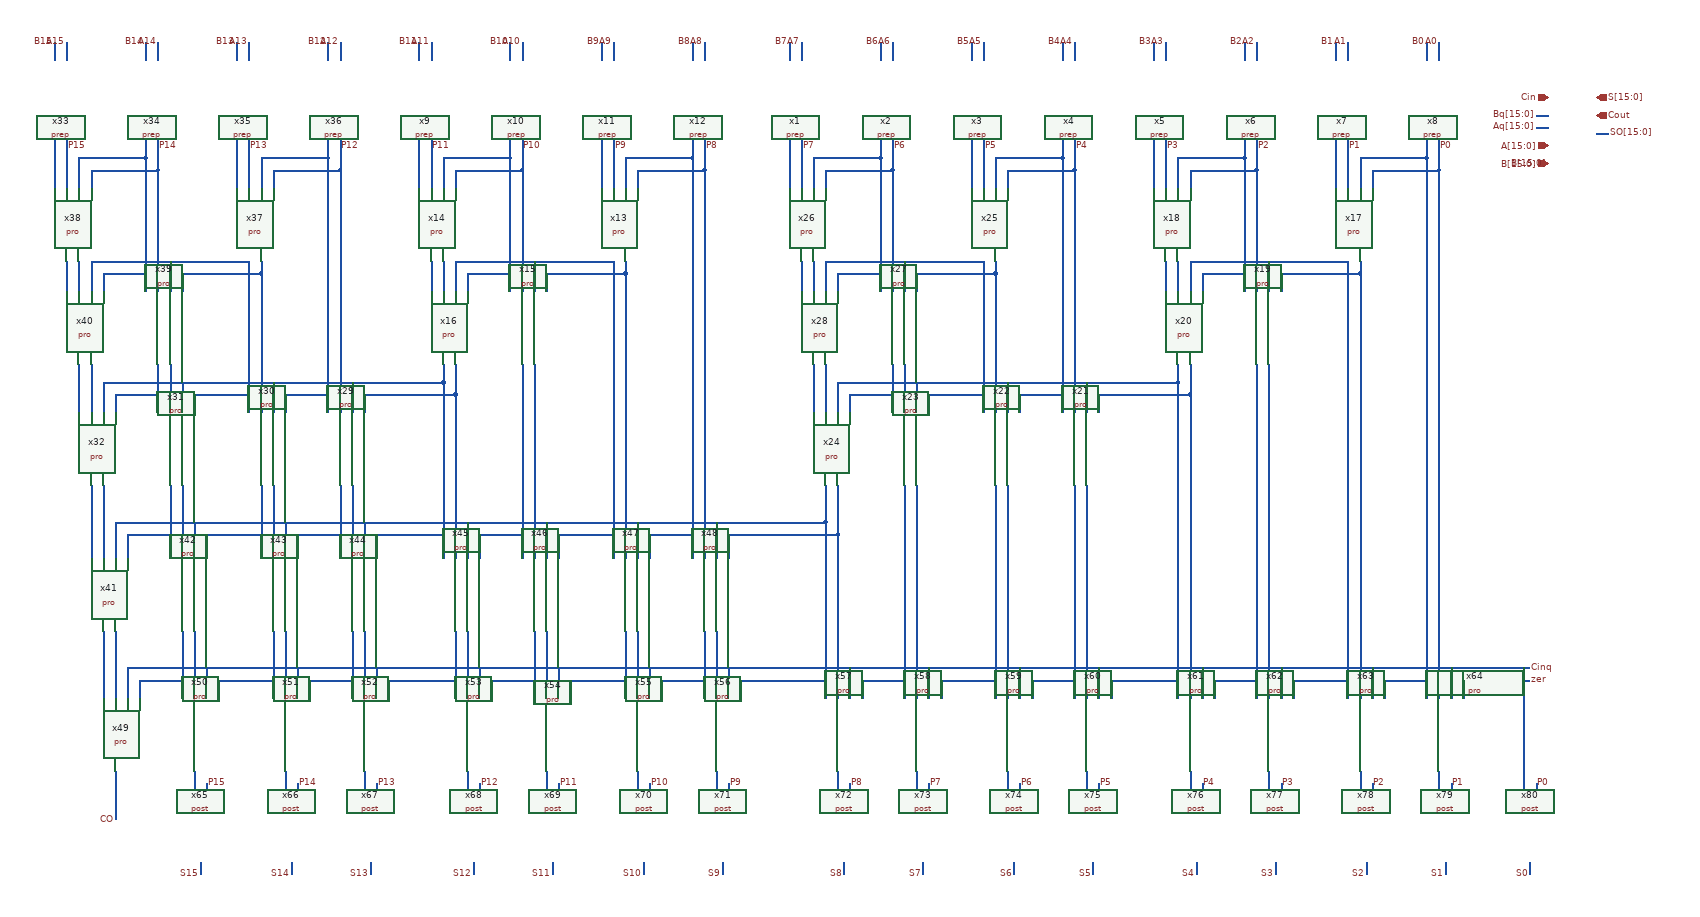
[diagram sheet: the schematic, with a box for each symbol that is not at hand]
v {xschem version=3.4.6 file_version=1.2}
G {}
K {}
V {}
S {}
E {}
N 1130 10 1130 60 {lab=P0}
N 1020 60 1020 90 {lab=P0}
N 1110 10 1110 40 {lab=#net1}
N 1000 40 1000 90 {lab=#net1}
N 980 10 980 90 {lab=P1}
N 960 10 960 90 {lab=#net2}
N 1000 40 1110 40 {lab=#net1}
N 1020 60 1130 60 {lab=P0}
N 660 10 660 90 {lab=#net3}
N 680 10 680 90 {lab=P3}
N 700 40 700 90 {lab=#net4}
N 700 40 810 40 {lab=#net4}
N 810 10 810 40 {lab=#net4}
N 830 10 830 60 {lab=P2}
N 720 60 830 60 {lab=P2}
N 720 60 720 90 {lab=P2}
N 680 210 680 260 {lab=#net5}
N 700 210 700 260 {lab=#net6}
N 720 210 720 260 {lab=#net7}
N 720 210 980 210 {lab=#net7}
N 740 230 740 260 {lab=#net8}
N 740 230 1000 230 {lab=#net8}
N 1000 210 1000 230 {lab=#net8}
N 810 40 810 250 {lab=#net4}
N 830 60 830 250 {lab=P2}
N 850 210 850 250 {lab=#net7}
N 530 10 530 60 {lab=P4}
N 420 60 420 90 {lab=P4}
N 510 10 510 40 {lab=#net9}
N 400 40 400 90 {lab=#net9}
N 380 10 380 90 {lab=P5}
N 360 10 360 90 {lab=#net10}
N 400 40 510 40 {lab=#net9}
N 420 60 530 60 {lab=P4}
N 60 10 60 90 {lab=#net11}
N 80 10 80 90 {lab=P7}
N 100 40 100 90 {lab=#net12}
N 100 40 210 40 {lab=#net12}
N 210 10 210 40 {lab=#net12}
N 230 10 230 60 {lab=P6}
N 120 60 230 60 {lab=P6}
N 120 60 120 90 {lab=P6}
N 80 210 80 260 {lab=#net13}
N 100 210 100 260 {lab=#net14}
N 120 210 120 260 {lab=#net15}
N 120 210 380 210 {lab=#net15}
N 140 230 140 260 {lab=#net16}
N 140 230 400 230 {lab=#net16}
N 400 210 400 230 {lab=#net16}
N 210 40 210 250 {lab=#net12}
N 230 60 230 250 {lab=P6}
N 250 210 250 250 {lab=#net15}
N 210 250 210 260 {lab=#net12}
N 230 250 230 260 {lab=P6}
N 250 250 250 260 {lab=#net15}
N 810 250 810 260 {lab=#net4}
N 830 250 830 260 {lab=P2}
N 850 250 850 260 {lab=#net7}
N 700 380 700 410 {lab=#net17}
N 140 410 700 410 {lab=#net17}
N 140 410 140 460 {lab=#net17}
N 720 380 720 430 {lab=#net18}
N 160 430 720 430 {lab=#net18}
N 160 430 160 460 {lab=#net18}
N 100 380 100 460 {lab=#net19}
N 120 380 120 460 {lab=#net20}
N 230 380 230 460 {lab=#net21}
N 250 380 250 460 {lab=#net22}
N 270 410 270 460 {lab=#net17}
N 290 430 290 460 {lab=#net18}
N 380 210 380 460 {lab=#net15}
N 400 230 400 460 {lab=#net16}
N 420 410 420 460 {lab=#net17}
N 440 430 440 460 {lab=#net18}
N 510 40 510 460 {lab=#net9}
N 530 60 530 460 {lab=P4}
N 550 410 550 460 {lab=#net17}
N 570 430 570 460 {lab=#net18}
N -80 10 -80 60 {lab=P8}
N -190 60 -190 90 {lab=P8}
N -100 10 -100 40 {lab=#net23}
N -210 40 -210 90 {lab=#net23}
N -230 10 -230 90 {lab=P9}
N -250 10 -250 90 {lab=#net24}
N -210 40 -100 40 {lab=#net23}
N -190 60 -80 60 {lab=P8}
N -550 10 -550 90 {lab=#net25}
N -530 10 -530 90 {lab=P11}
N -510 40 -510 90 {lab=#net26}
N -510 40 -400 40 {lab=#net26}
N -400 10 -400 40 {lab=#net26}
N -380 10 -380 60 {lab=P10}
N -490 60 -380 60 {lab=P10}
N -490 60 -490 90 {lab=P10}
N -530 210 -530 260 {lab=#net27}
N -510 210 -510 260 {lab=#net28}
N -490 210 -490 260 {lab=#net29}
N -490 210 -230 210 {lab=#net29}
N -470 230 -470 260 {lab=#net30}
N -470 230 -210 230 {lab=#net30}
N -210 210 -210 230 {lab=#net30}
N -400 40 -400 250 {lab=#net26}
N -380 60 -380 250 {lab=P10}
N -360 210 -360 250 {lab=#net29}
N -680 10 -680 60 {lab=P12}
N -790 60 -790 90 {lab=P12}
N -700 10 -700 40 {lab=#net31}
N -810 40 -810 90 {lab=#net31}
N -830 10 -830 90 {lab=P13}
N -850 10 -850 90 {lab=#net32}
N -810 40 -700 40 {lab=#net31}
N -790 60 -680 60 {lab=P12}
N -1150 10 -1150 90 {lab=#net33}
N -1130 10 -1130 90 {lab=P15}
N -1110 40 -1110 90 {lab=#net34}
N -1110 40 -1000 40 {lab=#net34}
N -1000 10 -1000 40 {lab=#net34}
N -980 10 -980 60 {lab=P14}
N -1090 60 -980 60 {lab=P14}
N -1090 60 -1090 90 {lab=P14}
N -1130 210 -1130 260 {lab=#net35}
N -1110 210 -1110 260 {lab=#net36}
N -1090 210 -1090 260 {lab=#net37}
N -1090 210 -830 210 {lab=#net37}
N -1070 230 -1070 260 {lab=#net38}
N -1070 230 -810 230 {lab=#net38}
N -810 210 -810 230 {lab=#net38}
N -1000 40 -1000 250 {lab=#net34}
N -980 60 -980 250 {lab=P14}
N -960 210 -960 250 {lab=#net37}
N -1000 250 -1000 260 {lab=#net34}
N -980 250 -980 260 {lab=P14}
N -960 250 -960 260 {lab=#net37}
N -400 250 -400 260 {lab=#net26}
N -380 250 -380 260 {lab=P10}
N -360 250 -360 260 {lab=#net29}
N -510 380 -510 410 {lab=#net39}
N -1070 410 -510 410 {lab=#net39}
N -1070 410 -1070 460 {lab=#net39}
N -490 380 -490 430 {lab=#net40}
N -1050 430 -490 430 {lab=#net40}
N -1050 430 -1050 460 {lab=#net40}
N -1110 380 -1110 460 {lab=#net41}
N -1090 380 -1090 460 {lab=#net42}
N -980 380 -980 460 {lab=#net43}
N -960 380 -960 460 {lab=#net44}
N -940 410 -940 460 {lab=#net39}
N -920 430 -920 460 {lab=#net40}
N -830 210 -830 460 {lab=#net37}
N -810 230 -810 460 {lab=#net38}
N -790 410 -790 460 {lab=#net39}
N -770 430 -770 460 {lab=#net40}
N -700 40 -700 460 {lab=#net31}
N -680 60 -680 460 {lab=P12}
N -660 410 -660 460 {lab=#net39}
N -640 430 -640 460 {lab=#net40}
N -1090 580 -1090 700 {lab=#net45}
N -1070 580 -1070 700 {lab=#net46}
N -960 580 -960 700 {lab=#net47}
N -940 580 -940 700 {lab=#net48}
N -810 580 -810 700 {lab=#net49}
N -790 580 -790 700 {lab=#net50}
N -680 580 -680 700 {lab=#net51}
N -660 580 -660 700 {lab=#net52}
N -510 410 -510 700 {lab=#net39}
N -490 430 -490 700 {lab=#net40}
N -380 380 -380 700 {lab=#net53}
N -360 380 -360 700 {lab=#net54}
N -230 210 -230 700 {lab=#net29}
N -210 230 -210 700 {lab=#net30}
N -100 40 -100 700 {lab=#net23}
N -80 60 -80 700 {lab=P8}
N 120 580 120 640 {lab=#net55}
N -1050 640 120 640 {lab=#net55}
N -1050 640 -1050 700 {lab=#net55}
N -1030 660 -1030 700 {lab=#net56}
N -1030 660 140 660 {lab=#net56}
N 140 580 140 660 {lab=#net56}
N -40 660 -40 700 {lab=#net56}
N -60 640 -60 700 {lab=#net55}
N -170 660 -170 700 {lab=#net56}
N -190 640 -190 700 {lab=#net55}
N -320 660 -320 700 {lab=#net56}
N -340 640 -340 700 {lab=#net55}
N -450 660 -450 700 {lab=#net56}
N -470 640 -470 700 {lab=#net55}
N -620 660 -620 700 {lab=#net56}
N -640 640 -640 700 {lab=#net55}
N -750 660 -750 700 {lab=#net56}
N -770 640 -770 700 {lab=#net55}
N -900 660 -900 700 {lab=#net56}
N -920 640 -920 700 {lab=#net55}
N -1070 820 -1070 930 {lab=#net57}
N -1050 820 -1050 930 {lab=#net58}
N -940 820 -940 930 {lab=#net59}
N -920 820 -920 930 {lab=#net60}
N -790 820 -790 930 {lab=#net61}
N -770 820 -770 930 {lab=#net62}
N -660 820 -660 930 {lab=#net63}
N -640 820 -640 930 {lab=#net64}
N -490 820 -490 930 {lab=#net65}
N -470 820 -470 930 {lab=#net66}
N -360 820 -360 940 {lab=#net67}
N -340 820 -340 930 {lab=#net68}
N -210 820 -210 930 {lab=#net69}
N -190 820 -190 930 {lab=#net70}
N -80 820 -80 930 {lab=#net71}
N -60 820 -60 930 {lab=#net72}
N 120 640 120 930 {lab=#net55}
N 140 660 140 930 {lab=#net56}
N 250 580 250 930 {lab=#net73}
N 270 580 270 930 {lab=#net74}
N 400 580 400 930 {lab=#net75}
N 420 580 420 930 {lab=#net76}
N 530 580 530 930 {lab=#net77}
N 550 580 550 930 {lab=#net78}
N 700 410 700 930 {lab=#net17}
N 720 430 720 930 {lab=#net18}
N 830 380 830 930 {lab=#net79}
N 850 380 850 930 {lab=#net80}
N 980 210 980 930 {lab=#net7}
N 1000 230 1000 930 {lab=#net8}
N 1110 40 1110 930 {lab=#net1}
N 1130 60 1130 930 {lab=P0}
N -1030 880 -1030 930 {lab=Cin}
N -1030 880 1280 880 {lab=Cin}
N -1010 900 -1010 930 {lab=zer}
N -1010 900 1280 900 {lab=zer}
N 1170 900 1170 930 {lab=zer}
N 1150 880 1150 930 {lab=Cin}
N 1040 900 1040 930 {lab=zer}
N 1020 880 1020 930 {lab=Cin}
N 890 900 890 930 {lab=zer}
N 870 880 870 930 {lab=Cin}
N 740 880 740 930 {lab=Cin}
N 760 900 760 930 {lab=zer}
N 590 900 590 930 {lab=zer}
N 570 880 570 930 {lab=Cin}
N 460 900 460 930 {lab=zer}
N 440 880 440 930 {lab=Cin}
N 310 900 310 930 {lab=zer}
N 290 880 290 930 {lab=Cin}
N 180 900 180 930 {lab=zer}
N 160 880 160 930 {lab=Cin}
N -20 900 -20 930 {lab=zer}
N -40 880 -40 930 {lab=Cin}
N -150 900 -150 930 {lab=zer}
N -170 880 -170 930 {lab=Cin}
N -300 900 -300 930 {lab=zer}
N -320 880 -320 930 {lab=Cin}
N -430 900 -430 930 {lab=zer}
N -450 880 -450 930 {lab=Cin}
N -600 900 -600 930 {lab=zer}
N -620 880 -620 930 {lab=Cin}
N -730 900 -730 930 {lab=zer}
N -750 880 -750 930 {lab=Cin}
N -880 900 -880 930 {lab=zer}
N -900 880 -900 930 {lab=Cin}
N -1050 1050 -1050 1130 {lab=Cout}
N -920 1050 -920 1080 {lab=#net81}
N -770 1050 -770 1080 {lab=#net82}
N -640 1050 -640 1080 {lab=#net83}
N -470 1050 -470 1080 {lab=#net84}
N -340 1050 -340 1080 {lab=#net85}
N -190 1050 -190 1080 {lab=#net86}
N -60 1050 -60 1080 {lab=#net87}
N 140 1050 140 1080 {lab=#net88}
N 270 1050 270 1080 {lab=#net89}
N 420 1050 420 1080 {lab=#net90}
N 550 1050 550 1080 {lab=#net91}
N 720 1050 720 1080 {lab=#net92}
N 850 1050 850 1080 {lab=#net93}
N 1000 1050 1000 1080 {lab=#net94}
N 1130 1050 1130 1080 {lab=#net95}
N -1150 -150 -1150 -120 {lab=B15}
N -1130 -150 -1130 -120 {lab=A15}
N -1000 -150 -1000 -120 {lab=B14}
N -980 -150 -980 -120 {lab=A14}
N -850 -150 -850 -120 {lab=B13}
N -830 -150 -830 -120 {lab=A13}
N -700 -150 -700 -120 {lab=B12}
N -680 -150 -680 -120 {lab=A12}
N -550 -150 -550 -120 {lab=B11}
N -530 -150 -530 -120 {lab=A11}
N -400 -150 -400 -120 {lab=B10}
N -380 -150 -380 -120 {lab=A10}
N -250 -150 -250 -120 {lab=B9}
N -230 -150 -230 -120 {lab=A9}
N -100 -150 -100 -120 {lab=B8}
N -80 -150 -80 -120 {lab=A8}
N 60 -150 60 -120 {lab=B7}
N 80 -150 80 -120 {lab=A7}
N 210 -150 210 -120 {lab=B6}
N 230 -150 230 -120 {lab=A6}
N 360 -150 360 -120 {lab=B5}
N 380 -150 380 -120 {lab=A5}
N 510 -150 510 -120 {lab=B4}
N 530 -150 530 -120 {lab=A4}
N 660 -150 660 -120 {lab=B3}
N 680 -150 680 -120 {lab=A3}
N 810 -150 810 -120 {lab=B2}
N 830 -150 830 -120 {lab=A2}
N 960 -150 960 -120 {lab=B1}
N 980 -150 980 -120 {lab=A1}
N 1110 -150 1110 -120 {lab=B0}
N 1130 -150 1130 -120 {lab=A0}
N 1270 880 1270 1080 {lab=Cin}
N 1290 1070 1290 1080 {lab=P0}
N 1150 1070 1150 1080 {lab=P1}
N 1020 1070 1020 1080 {lab=P2}
N 870 1070 870 1080 {lab=P3}
N 740 1070 740 1080 {lab=P4}
N 570 1070 570 1080 {lab=P5}
N 440 1070 440 1080 {lab=P6}
N 290 1070 290 1080 {lab=P7}
N 160 1070 160 1080 {lab=P8}
N -40 1070 -40 1080 {lab=P9}
N -170 1070 -170 1080 {lab=P10}
N -320 1070 -320 1080 {lab=P11}
N -450 1070 -450 1080 {lab=P12}
N -620 1070 -620 1080 {lab=P13}
N -750 1070 -750 1080 {lab=P14}
N -900 1070 -900 1080 {lab=P15}
N 1280 1200 1280 1220 {lab=S0}
N 1140 1200 1140 1220 {lab=S1}
N 1010 1200 1010 1220 {lab=S2}
N 860 1200 860 1220 {lab=S3}
N 730 1200 730 1220 {lab=S4}
N 560 1200 560 1220 {lab=S5}
N 430 1200 430 1220 {lab=S6}
N 280 1200 280 1220 {lab=S7}
N 150 1200 150 1220 {lab=S8}
N -50 1200 -50 1220 {lab=S9}
N -180 1200 -180 1220 {lab=S10}
N -330 1200 -330 1220 {lab=S11}
N -460 1200 -460 1220 {lab=S12}
N -630 1200 -630 1220 {lab=S13}
N -760 1200 -760 1220 {lab=S14}
N -910 1200 -910 1220 {lab=S15}
N 270 230 270 260 {lab=#net16}
N -940 230 -940 260 {lab=#net38}
N -340 230 -340 260 {lab=#net30}
N 870 230 870 260 {lab=#net8}
N 1290 -10 1310 -10 {lab=#net96}
N 1290 -30 1310 -30 {lab=#net97}
N 1390 0 1410 0 {lab=#net97}
C {/home/EE23B038/ee5311/tutorial_9/prep.sym} 660 -40 0 0 {name=x5}
C {/home/EE23B038/ee5311/tutorial_9/prep.sym} 810 -40 0 0 {name=x6}
C {/home/EE23B038/ee5311/tutorial_9/prep.sym} 960 -40 0 0 {name=x7}
C {/home/EE23B038/ee5311/tutorial_9/prep.sym} 1110 -40 0 0 {name=x8}
C {/home/EE23B038/ee5311/tutorial_9/pro.sym} 970 160 0 0 {name=x17}
C {/home/EE23B038/ee5311/tutorial_9/pro.sym} 670 160 0 0 {name=x18}
C {/home/EE23B038/ee5311/tutorial_9/pro.sym} 820 330 0 0 {name=x19}
C {/home/EE23B038/ee5311/tutorial_9/pro.sym} 690 330 0 0 {name=x20}
C {/home/EE23B038/ee5311/tutorial_9/pro.sym} 520 530 0 0 {name=x21}
C {/home/EE23B038/ee5311/tutorial_9/pro.sym} 390 530 0 0 {name=x22}
C {/home/EE23B038/ee5311/tutorial_9/pro.sym} 240 530 0 0 {name=x23}
C {/home/EE23B038/ee5311/tutorial_9/pro.sym} 110 530 0 0 {name=x24}
C {/home/EE23B038/ee5311/tutorial_9/prep.sym} 60 -40 0 0 {name=x1}
C {/home/EE23B038/ee5311/tutorial_9/prep.sym} 210 -40 0 0 {name=x2}
C {/home/EE23B038/ee5311/tutorial_9/prep.sym} 360 -40 0 0 {name=x3}
C {/home/EE23B038/ee5311/tutorial_9/prep.sym} 510 -40 0 0 {name=x4}
C {/home/EE23B038/ee5311/tutorial_9/pro.sym} 370 160 0 0 {name=x25}
C {/home/EE23B038/ee5311/tutorial_9/pro.sym} 70 160 0 0 {name=x26}
C {/home/EE23B038/ee5311/tutorial_9/pro.sym} 220 330 0 0 {name=x27}
C {/home/EE23B038/ee5311/tutorial_9/pro.sym} 90 330 0 0 {name=x28}
C {/home/EE23B038/ee5311/tutorial_9/prep.sym} -550 -40 0 0 {name=x9}
C {/home/EE23B038/ee5311/tutorial_9/prep.sym} -400 -40 0 0 {name=x10}
C {/home/EE23B038/ee5311/tutorial_9/prep.sym} -250 -40 0 0 {name=x11}
C {/home/EE23B038/ee5311/tutorial_9/prep.sym} -100 -40 0 0 {name=x12}
C {/home/EE23B038/ee5311/tutorial_9/pro.sym} -240 160 0 0 {name=x13}
C {/home/EE23B038/ee5311/tutorial_9/pro.sym} -540 160 0 0 {name=x14}
C {/home/EE23B038/ee5311/tutorial_9/pro.sym} -390 330 0 0 {name=x15}
C {/home/EE23B038/ee5311/tutorial_9/pro.sym} -520 330 0 0 {name=x16}
C {/home/EE23B038/ee5311/tutorial_9/pro.sym} -690 530 0 0 {name=x29}
C {/home/EE23B038/ee5311/tutorial_9/pro.sym} -820 530 0 0 {name=x30}
C {/home/EE23B038/ee5311/tutorial_9/pro.sym} -970 530 0 0 {name=x31}
C {/home/EE23B038/ee5311/tutorial_9/pro.sym} -1100 530 0 0 {name=x32}
C {/home/EE23B038/ee5311/tutorial_9/prep.sym} -1150 -40 0 0 {name=x33}
C {/home/EE23B038/ee5311/tutorial_9/prep.sym} -1000 -40 0 0 {name=x34}
C {/home/EE23B038/ee5311/tutorial_9/prep.sym} -850 -40 0 0 {name=x35}
C {/home/EE23B038/ee5311/tutorial_9/prep.sym} -700 -40 0 0 {name=x36}
C {/home/EE23B038/ee5311/tutorial_9/pro.sym} -840 160 0 0 {name=x37}
C {/home/EE23B038/ee5311/tutorial_9/pro.sym} -1140 160 0 0 {name=x38}
C {/home/EE23B038/ee5311/tutorial_9/pro.sym} -990 330 0 0 {name=x39}
C {/home/EE23B038/ee5311/tutorial_9/pro.sym} -1120 330 0 0 {name=x40}
C {/home/EE23B038/ee5311/tutorial_9/pro.sym} -1080 770 0 0 {name=x41}
C {/home/EE23B038/ee5311/tutorial_9/pro.sym} -950 770 0 0 {name=x42}
C {/home/EE23B038/ee5311/tutorial_9/pro.sym} -800 770 0 0 {name=x43}
C {/home/EE23B038/ee5311/tutorial_9/pro.sym} -670 770 0 0 {name=x44}
C {/home/EE23B038/ee5311/tutorial_9/pro.sym} -500 770 0 0 {name=x45}
C {/home/EE23B038/ee5311/tutorial_9/pro.sym} -370 770 0 0 {name=x46}
C {/home/EE23B038/ee5311/tutorial_9/pro.sym} -220 770 0 0 {name=x47}
C {/home/EE23B038/ee5311/tutorial_9/pro.sym} -90 770 0 0 {name=x48}
C {/home/EE23B038/ee5311/tutorial_9/pro.sym} -1060 1000 0 0 {name=x49}
C {/home/EE23B038/ee5311/tutorial_9/pro.sym} -930 1000 0 0 {name=x50}
C {/home/EE23B038/ee5311/tutorial_9/pro.sym} -780 1000 0 0 {name=x51}
C {/home/EE23B038/ee5311/tutorial_9/pro.sym} -650 1000 0 0 {name=x52}
C {/home/EE23B038/ee5311/tutorial_9/pro.sym} -480 1000 0 0 {name=x53}
C {/home/EE23B038/ee5311/tutorial_9/pro.sym} -350 1000 0 0 {name=x54}
C {/home/EE23B038/ee5311/tutorial_9/pro.sym} -200 1000 0 0 {name=x55}
C {/home/EE23B038/ee5311/tutorial_9/pro.sym} -70 1000 0 0 {name=x56}
C {/home/EE23B038/ee5311/tutorial_9/pro.sym} 130 1000 0 0 {name=x57}
C {/home/EE23B038/ee5311/tutorial_9/pro.sym} 260 1000 0 0 {name=x58}
C {/home/EE23B038/ee5311/tutorial_9/pro.sym} 410 1000 0 0 {name=x59}
C {/home/EE23B038/ee5311/tutorial_9/pro.sym} 540 1000 0 0 {name=x60}
C {/home/EE23B038/ee5311/tutorial_9/pro.sym} 710 1000 0 0 {name=x61}
C {/home/EE23B038/ee5311/tutorial_9/pro.sym} 840 1000 0 0 {name=x62}
C {/home/EE23B038/ee5311/tutorial_9/pro.sym} 990 1000 0 0 {name=x63}
C {/home/EE23B038/ee5311/tutorial_9/pro.sym} 1120 1000 0 0 {name=x64}
C {ipin.sym} 1310 -60 0 0 {name=p1 lab=Cin verilog_type=logic}
C {lab_pin.sym} 1280 900 2 0 {name=p2 verilog_type=logic lab=zer}
C {noconn.sym} 1310 -60 1 0 {name=l2}
C {ipin.sym} 1310 20 0 0 {name=p4 lab=A[15:0] verilog_type=logic}
C {noconn.sym} 1310 20 1 0 {name=l3}
C {ipin.sym} 1310 50 0 0 {name=p5 lab=B[15:0] verilog_type=logic}
C {noconn.sym} 1310 50 1 0 {name=l4
lab=B[15:0]}
C {/home/EE23B038/ee5311/tutorial_9/post.sym} -910 1150 0 0 {name=x65}
C {/home/EE23B038/ee5311/tutorial_9/post.sym} -760 1150 0 0 {name=x66}
C {/home/EE23B038/ee5311/tutorial_9/post.sym} -630 1150 0 0 {name=x67}
C {/home/EE23B038/ee5311/tutorial_9/post.sym} -460 1150 0 0 {name=x68}
C {/home/EE23B038/ee5311/tutorial_9/post.sym} -330 1150 0 0 {name=x69}
C {/home/EE23B038/ee5311/tutorial_9/post.sym} -180 1150 0 0 {name=x70}
C {/home/EE23B038/ee5311/tutorial_9/post.sym} -50 1150 0 0 {name=x71}
C {/home/EE23B038/ee5311/tutorial_9/post.sym} 150 1150 0 0 {name=x72}
C {/home/EE23B038/ee5311/tutorial_9/post.sym} 280 1150 0 0 {name=x73}
C {/home/EE23B038/ee5311/tutorial_9/post.sym} 430 1150 0 0 {name=x74}
C {/home/EE23B038/ee5311/tutorial_9/post.sym} 560 1150 0 0 {name=x75}
C {/home/EE23B038/ee5311/tutorial_9/post.sym} 730 1150 0 0 {name=x76}
C {/home/EE23B038/ee5311/tutorial_9/post.sym} 860 1150 0 0 {name=x77}
C {/home/EE23B038/ee5311/tutorial_9/post.sym} 1010 1150 0 0 {name=x78}
C {/home/EE23B038/ee5311/tutorial_9/post.sym} 1140 1150 0 0 {name=x79}
C {opin.sym} 1390 -60 0 0 {name=p6 lab=S[15:0] verilog_type=logic}
C {noconn.sym} 1390 -60 1 0 {name=l5}
C {lab_pin.sym} -1150 -150 1 0 {name=p7 verilog_type=logic lab=B15}
C {lab_pin.sym} -1130 -150 1 0 {name=p8 verilog_type=logic lab=A15}
C {lab_pin.sym} -1000 -150 1 0 {name=p9 verilog_type=logic lab=B14}
C {lab_pin.sym} -980 -150 1 0 {name=p10 verilog_type=logic lab=A14}
C {lab_pin.sym} -850 -150 1 0 {name=p11 verilog_type=logic lab=B13}
C {lab_pin.sym} -830 -150 1 0 {name=p12 verilog_type=logic lab=A13}
C {lab_pin.sym} -700 -150 1 0 {name=p13 verilog_type=logic lab=B12}
C {lab_pin.sym} -680 -150 1 0 {name=p14 verilog_type=logic lab=A12}
C {lab_pin.sym} -550 -150 1 0 {name=p15 verilog_type=logic lab=B11}
C {lab_pin.sym} -530 -150 1 0 {name=p16 verilog_type=logic lab=A11}
C {lab_pin.sym} -400 -150 1 0 {name=p17 verilog_type=logic lab=B10}
C {lab_pin.sym} -380 -150 1 0 {name=p18 verilog_type=logic lab=A10}
C {lab_pin.sym} -250 -150 1 0 {name=p19 verilog_type=logic lab=B9}
C {lab_pin.sym} -230 -150 1 0 {name=p20 verilog_type=logic lab=A9}
C {lab_pin.sym} -100 -150 1 0 {name=p21 verilog_type=logic lab=B8}
C {lab_pin.sym} -80 -150 1 0 {name=p22 verilog_type=logic lab=A8}
C {lab_pin.sym} 60 -150 1 0 {name=p23 verilog_type=logic lab=B7}
C {lab_pin.sym} 80 -150 1 0 {name=p24 verilog_type=logic lab=A7}
C {lab_pin.sym} 210 -150 1 0 {name=p25 verilog_type=logic lab=B6}
C {lab_pin.sym} 230 -150 1 0 {name=p26 verilog_type=logic lab=A6}
C {lab_pin.sym} 360 -150 1 0 {name=p27 verilog_type=logic lab=B5}
C {lab_pin.sym} 380 -150 1 0 {name=p28 verilog_type=logic lab=A5}
C {lab_pin.sym} 510 -150 1 0 {name=p29 verilog_type=logic lab=B4}
C {lab_pin.sym} 530 -150 1 0 {name=p30 verilog_type=logic lab=A4}
C {lab_pin.sym} 660 -150 1 0 {name=p31 verilog_type=logic lab=B3}
C {lab_pin.sym} 680 -150 1 0 {name=p32 verilog_type=logic lab=A3}
C {lab_pin.sym} 810 -150 1 0 {name=p33 verilog_type=logic lab=B2}
C {lab_pin.sym} 830 -150 1 0 {name=p34 verilog_type=logic lab=A2}
C {lab_pin.sym} 960 -150 1 0 {name=p35 verilog_type=logic lab=B1}
C {lab_pin.sym} 980 -150 1 0 {name=p36 verilog_type=logic lab=A1}
C {lab_pin.sym} 1110 -150 1 0 {name=p37 verilog_type=logic lab=B0}
C {lab_pin.sym} 1130 -150 1 0 {name=p38 verilog_type=logic lab=A0}
C {lab_pin.sym} 1130 20 2 0 {name=p39 verilog_type=logic lab=P0}
C {lab_pin.sym} 980 20 2 0 {name=p40 verilog_type=logic lab=P1}
C {lab_pin.sym} 830 20 2 0 {name=p41 verilog_type=logic lab=P2}
C {lab_pin.sym} 680 20 2 0 {name=p42 verilog_type=logic lab=P3}
C {lab_pin.sym} 530 20 2 0 {name=p43 verilog_type=logic lab=P4}
C {lab_pin.sym} 380 20 2 0 {name=p44 verilog_type=logic lab=P5}
C {lab_pin.sym} 230 20 2 0 {name=p45 verilog_type=logic lab=P6}
C {lab_pin.sym} 80 20 2 0 {name=p46 verilog_type=logic lab=P7}
C {lab_pin.sym} -80 20 2 0 {name=p47 verilog_type=logic lab=P8}
C {lab_pin.sym} -230 20 2 0 {name=p48 verilog_type=logic lab=P9}
C {lab_pin.sym} -380 20 2 0 {name=p49 verilog_type=logic lab=P10}
C {lab_pin.sym} -530 20 2 0 {name=p50 verilog_type=logic lab=P11}
C {lab_pin.sym} -680 20 2 0 {name=p51 verilog_type=logic lab=P12}
C {lab_pin.sym} -830 20 2 0 {name=p52 verilog_type=logic lab=P13}
C {lab_pin.sym} -980 20 2 0 {name=p53 verilog_type=logic lab=P14}
C {lab_pin.sym} -1130 20 2 0 {name=p54 verilog_type=logic lab=P15}
C {lab_pin.sym} -450 1070 2 0 {name=p55 verilog_type=logic lab=P12}
C {lab_pin.sym} -620 1070 2 0 {name=p56 verilog_type=logic lab=P13}
C {lab_pin.sym} -750 1070 2 0 {name=p57 verilog_type=logic lab=P14}
C {lab_pin.sym} -900 1070 2 0 {name=p58 verilog_type=logic lab=P15}
C {lab_pin.sym} 160 1070 2 0 {name=p59 verilog_type=logic lab=P8}
C {lab_pin.sym} -40 1070 2 0 {name=p60 verilog_type=logic lab=P9}
C {lab_pin.sym} -170 1070 2 0 {name=p61 verilog_type=logic lab=P10}
C {lab_pin.sym} -320 1070 2 0 {name=p62 verilog_type=logic lab=P11}
C {lab_pin.sym} 1020 1070 2 0 {name=p63 verilog_type=logic lab=P2}
C {lab_pin.sym} 870 1070 2 0 {name=p64 verilog_type=logic lab=P3}
C {lab_pin.sym} 740 1070 2 0 {name=p65 verilog_type=logic lab=P4}
C {lab_pin.sym} 570 1070 2 0 {name=p66 verilog_type=logic lab=P5}
C {lab_pin.sym} 440 1070 2 0 {name=p67 verilog_type=logic lab=P6}
C {lab_pin.sym} 290 1070 2 0 {name=p68 verilog_type=logic lab=P7}
C {lab_pin.sym} 1290 1070 2 0 {name=p69 verilog_type=logic lab=P0}
C {lab_pin.sym} 1150 1070 2 0 {name=p70 verilog_type=logic lab=P1}
C {/home/EE23B038/ee5311/tutorial_9/post.sym} 1280 1150 0 0 {name=x80}
C {lab_pin.sym} 1280 1220 0 0 {name=p71 verilog_type=logic lab=S0}
C {lab_pin.sym} 1140 1220 0 0 {name=p72 verilog_type=logic lab=S1}
C {lab_pin.sym} 1010 1220 0 0 {name=p73 verilog_type=logic lab=S2}
C {lab_pin.sym} 860 1220 0 0 {name=p74 verilog_type=logic lab=S3}
C {lab_pin.sym} 730 1220 0 0 {name=p75 verilog_type=logic lab=S4}
C {lab_pin.sym} 560 1220 0 0 {name=p76 verilog_type=logic lab=S5}
C {lab_pin.sym} 430 1220 0 0 {name=p77 verilog_type=logic lab=S6}
C {lab_pin.sym} 280 1220 0 0 {name=p78 verilog_type=logic lab=S7}
C {lab_pin.sym} 150 1220 0 0 {name=p79 verilog_type=logic lab=S8}
C {lab_pin.sym} -50 1220 0 0 {name=p80 verilog_type=logic lab=S9}
C {lab_pin.sym} -180 1220 0 0 {name=p81 verilog_type=logic lab=S10}
C {lab_pin.sym} -330 1220 0 0 {name=p82 verilog_type=logic lab=S11}
C {lab_pin.sym} -460 1220 0 0 {name=p83 verilog_type=logic lab=S12}
C {lab_pin.sym} -630 1220 0 0 {name=p84 verilog_type=logic lab=S13}
C {lab_pin.sym} -760 1220 0 0 {name=p85 verilog_type=logic lab=S14}
C {lab_pin.sym} -910 1220 0 0 {name=p86 verilog_type=logic lab=S15}
C {verilog_code.sym} 1210 160 0 0 {name=s1 string="assign \{A15,A14,A13,A12,A11,A10,A9,A8,A7,A6,A5,A4,A3,A2,A1,A0\} = Aq[15:0];
assign \{B15,B14,B13,B12,B11,B10,B9,B8,B7,B6,B5,B4,B3,B2,B1,B0\} = Bq[15:0];
assign SO[15:0] = \{S15,S14,S13,S12,S11,S10,S9,S8,S7,S6,S5,S4,S3,S2,S1,S0\};
assign zer = 0;
always @(posedge CLK) begin
Aq <= A;
Bq <= B;
Cinq <= Cin;
S <= SO;
Cout <= CO;
end"}
C {noconn.sym} -1150 -120 0 0 {name=l6}
C {noconn.sym} -1130 -120 0 0 {name=l7}
C {noconn.sym} -1000 -120 0 0 {name=l8}
C {noconn.sym} -980 -120 0 0 {name=l9}
C {noconn.sym} -850 -120 0 0 {name=l10}
C {noconn.sym} -830 -120 0 0 {name=l11}
C {noconn.sym} -700 -120 0 0 {name=l12}
C {noconn.sym} -680 -120 0 0 {name=l13}
C {noconn.sym} -550 -120 0 0 {name=l14}
C {noconn.sym} -530 -120 0 0 {name=l15}
C {noconn.sym} -400 -120 0 0 {name=l16}
C {noconn.sym} -380 -120 0 0 {name=l17}
C {noconn.sym} -250 -120 0 0 {name=l18}
C {noconn.sym} -230 -120 0 0 {name=l19}
C {noconn.sym} -100 -120 0 0 {name=l20}
C {noconn.sym} -80 -120 0 0 {name=l21}
C {noconn.sym} 60 -120 0 0 {name=l22}
C {noconn.sym} 80 -120 0 0 {name=l23}
C {noconn.sym} 210 -120 0 0 {name=l24}
C {noconn.sym} 230 -120 0 0 {name=l25}
C {noconn.sym} 360 -120 0 0 {name=l26}
C {noconn.sym} 380 -120 0 0 {name=l27}
C {noconn.sym} 510 -120 0 0 {name=l28}
C {noconn.sym} 530 -120 0 0 {name=l29}
C {noconn.sym} 660 -120 0 0 {name=l30}
C {noconn.sym} 680 -120 0 0 {name=l31}
C {noconn.sym} 810 -120 0 0 {name=l32}
C {noconn.sym} 830 -120 0 0 {name=l33}
C {noconn.sym} 960 -120 0 0 {name=l34}
C {noconn.sym} 980 -120 0 0 {name=l35}
C {noconn.sym} 1110 -120 0 0 {name=l36}
C {noconn.sym} 1130 -120 0 0 {name=l37}
C {noconn.sym} -910 1200 0 0 {name=l38}
C {noconn.sym} -760 1200 0 0 {name=l39}
C {noconn.sym} -630 1200 0 0 {name=l40}
C {noconn.sym} -460 1200 0 0 {name=l41}
C {noconn.sym} -330 1200 0 0 {name=l42}
C {noconn.sym} -180 1200 0 0 {name=l43}
C {noconn.sym} -50 1200 0 0 {name=l44}
C {noconn.sym} 150 1200 0 0 {name=l45}
C {noconn.sym} 280 1200 0 0 {name=l46}
C {noconn.sym} 430 1200 0 0 {name=l47}
C {noconn.sym} 560 1200 0 0 {name=l48}
C {noconn.sym} 730 1200 0 0 {name=l49}
C {noconn.sym} 860 1200 0 0 {name=l50}
C {noconn.sym} 1010 1200 0 0 {name=l51}
C {noconn.sym} 1140 1200 0 0 {name=l52}
C {noconn.sym} 1280 1200 0 0 {name=l53}
C {noconn.sym} 1280 900 3 0 {name=l54}
C {lab_pin.sym} 1290 -10 0 0 {name=p87 verilog_type=logic lab=Aq[15:0]}
C {lab_pin.sym} 1290 -30 0 0 {name=p88 verilog_type=logic lab=Bq[15:0]}
C {noconn.sym} 1310 -10 1 0 {name=l55}
C {noconn.sym} 1310 -30 1 0 {name=l56}
C {lab_pin.sym} 1280 880 2 0 {name=p89 verilog_type=logic lab=Cinq}
C {noconn.sym} 1280 880 1 0 {name=l57}
C {lab_pin.sym} -1050 1130 3 0 {name=p90 verilog_type=logic lab=CO}
C {opin.sym} 1390 -30 0 0 {name=p3 lab=Cout}
C {noconn.sym} 1390 -30 1 0 {name=l1}
C {lab_pin.sym} 1410 0 2 0 {name=p91 verilog_type=logic lab=SO[15:0]}
C {noconn.sym} 1390 0 1 0 {name=l58}
